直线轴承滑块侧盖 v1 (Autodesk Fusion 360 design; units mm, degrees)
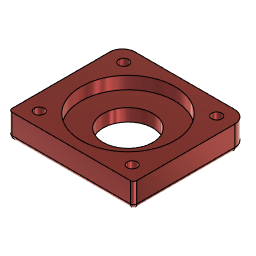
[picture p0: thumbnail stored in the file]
base_feature "基础特征"
fillet "圆角" radius 0.75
